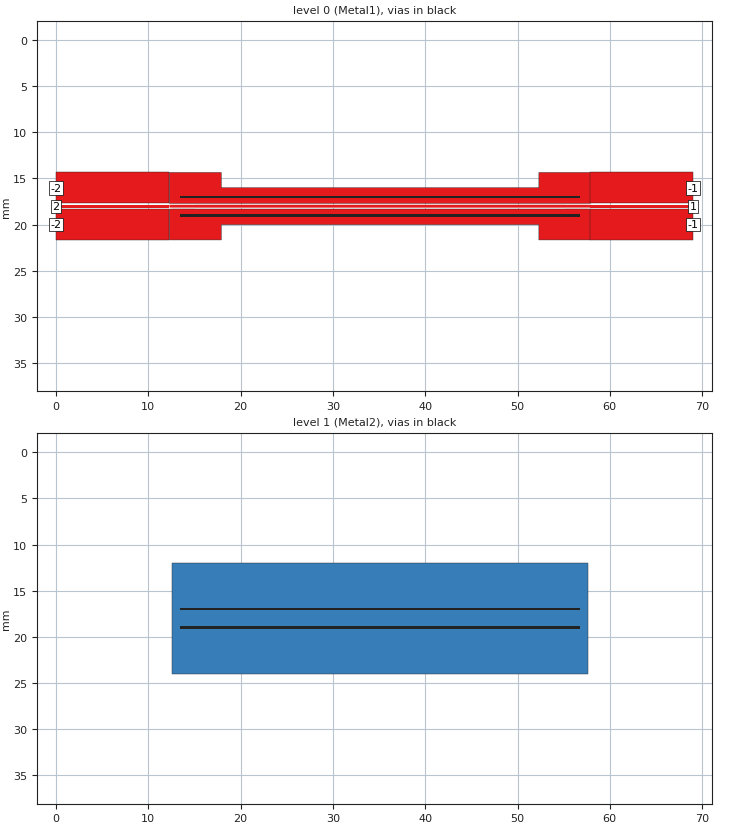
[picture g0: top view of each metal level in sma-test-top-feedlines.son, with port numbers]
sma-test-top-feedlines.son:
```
FTYP SONPROJ 18 ! Sonnet Project File
VER 17.56
HEADER
LIC antikernel2.1.50170 ac1f6b6437c5 havequick azonenberg Level3Gold
DAT 04/11/2021 07:41:37
BUILT_BY_CREATED dxf 17.52.2 05/01/2020 05:35:06
BUILT_BY_SAVED sonnet 17.56
MDATE 04/11/2021 07:41:05
HDATE 04/11/2021 07:41:05
ANN Created by dxfgeo, Sonnet Software Inc.
END HEADER
DIM
ANG DEG
CAP PF
CON /OH
FREQ GHZ
IND NH
LNG MM
RES OH
END DIM
CONTROL
VARSWP
OPTIONS  -dj
SPEED 1
CACHE_ABS 1
Q_ACC N
END CONTROL
GEO
SYM
DRP1 LEFT LINK
POLY 458 1
20
DRP1 RIGHT LINK
POLY 1025 1
0
TMET "Free Space" 0 FREESPACE 376.7303136 0 0 0
BMET "Free Space" 0 FREESPACE 376.7303136 0 0 0
MET "Copper 1oz thick" 2 TMM 58000000 0.5 0.035 2
MET "Nickel " 3 TMM 14300000 0.5 3.5e-05 2
MET "Copper 0.5oz" 1 NOR 58000000 0.5 0.0175 
MET "Unknown_metal" 1 NOR INF 0.5 0 
MET "Unknown_metal" 1 VOL INF 0
BRI "Alumina (96%)" 0 9.4 0.0004 0 
BRI "Alumina (99.5%)" 0 9.9 0.0001 0 
BRI "Aluminum Nitride" 0 8.6 0.0003 0 
BRI "Arlon 25FR" 0 3.58 0.0035 0 
BRI "Arlon 25N" 0 3.38 0.0025 0 
BRI "Arlon AD5" 0 5.1 0.003 0 
BRI "Arlon AD10" 0 10.2 0.005 0 
BRI "Arlon AD250" 0 2.5 0.0018 0 
BRI "Arlon AD255A" 0 2.55 0.0015 0 
BRI "Arlon AD260A" 0 2.6 0.0018 0 
BRI "Arlon AD270" 0 2.7 0.0023 0 
BRI "Arlon AD300A" 0 3 0.002 0 
BRI "Arlon AD320A" 0 3.2 0.0032 0 
BRI "Arlon AD350A" 0 3.5 0.003 0 
BRI "Arlon AD410" 0 4.1 0.003 0 
BRI "Arlon AD430" 0 4.3 0.003 0 
BRI "Arlon AD450" 0 4.5 0.0035 0 
BRI "Arlon AD600" 0 6.15 0.003 0 
BRI "Arlon AD1000" 0 10.2 0.0023 0 
BRI "Arlon AR1000" 0 9.8 0.003 0 
BRI "Arlon CLTE" 0 2.96 0.0023 0 
BRI "Arlon CLTE-AT" 0 3 0.0013 0 
BRI "Arlon CLTE-P" 0 2.94 0.0025 0 
BRI "Arlon CLTE-XT" 0 2.94 0.0012 0 
BRI "Arlon Cu 217LX" 0 2.17 0.0009 0 
BRI "Arlon Cu 233LX" 0 2.33 0.0013 0 
BRI "Arlon Cu 250GT" 0 2.5 0.001 0 
BRI "Arlon Cu 250GX" 0 2.5 0.0018 0 
BRI "Arlon Cu 6250" 0 2.32 0.0013 0 
BRI "Arlon Cu 6700" 0 2.35 0.0025 0 
BRI "Arlon Di 522" 0 2.5 0.001 0 
BRI "Arlon Di 527" 0 2.5 0.0018 0 
BRI "Arlon Di 870" 0 2.33 0.0013 0 
BRI "Arlon Di 880" 0 2.17 0.0009 0 
BRI "Arlon Iso 917" 0 2.17 0.0013 0 
BRI "Arlon Iso 933" 0 2.33 0.0016 0 
BRI "Arlon Multi HF" 0 3.7 0.004 0 
BRI "Arlon TC350" 0 3.5 0.002 0 
BRI "Arlon TC600" 0 6.15 0.002 0 
BRI "Beryllia (99.5%)" 0 6.5 0.0004 0 
BRI "CEM-1" 0 4.5 0.02 0 
BRI "CEM-3" 0 4.5 0.02 0 
BRI "Dupont 9K7" 0 7.1 0.0012 0 
BRI "Dupont 943" 0 7.4 0.002 0 
BRI "Dupont 951" 0 7.8 0.006 0 
BRI "Dupont FEP" 0 2 0.0005 0 
BRI "Dupont Vacrel" 0 3.8 0.011 0 
BRI "ESL 41010" 0 7.5 0.005 0 
BRI "ESL 41020" 0 7.25 0.005 0 
BRI "ESL 41050" 0 13.5 0.002 0 
BRI "ESL 41060" 0 16.5 0.002 0 
BRI "ESL 41110" 0 4.5 0.004 0 
BRI "Ferro A6M" 0 5.9 0.002 0 
BRI "Ferro A6S" 0 5.9 0.002 0 
BRI "Ferro L8" 0 7.3 0.0018 0 
BRI "FR-4" 0 4.4 0.02 0 
BRI "G-10" 0 4.8 0.025 0 
BRI "Gallium Arsenide" 0 12.9 0.006 0 
BRI "Gallium Nitride" 0 9.7 0 0 
BRI "Glass (Pyrex)" 0 4.82 0.0054 0 
BRI "Heraeus HL2000" 0 7.3 0.0026 0 
BRI "Isola 370HR" 0 4.04 0.021 0 
BRI "Isola FR408" 0 3.77 0.0116 0 
BRI "Isola FR408HR" 0 3.68 0.0092 0 
BRI "Isola Getek" 0 3.6 0.01 0 
BRI "Isola GI-180" 0 3.7 0.013 0 
BRI "Isola IS415" 0 3.82 0.0125 0 
BRI "Isola IS620i" 0 3.58 0.006 0 
BRI "Isola IS680-280" 0 2.8 0.0025 0 
BRI "Isola IS680-300" 0 3 0.003 0 
BRI "Isola IS680-320" 0 3.2 0.003 0 
BRI "Isola IS680-333" 0 3.33 0.003 0 
BRI "Isola IS680-338" 0 3.38 0.0032 0 
BRI "Isola IS680-345" 0 3.45 0.0036 0 
BRI "Kerafol CT800" 0 5.3 0.008 0 
BRI "Nelco MW9350" 0 3.7 0.004 0 
BRI "Nelco N4000-12" 0 3.7 0.008 0 
BRI "Nelco N4000-13" 0 3.7 0.009 0 
BRI "Nelco N4000-13SI" 0 3.2 0.007 0 
BRI "Nelco N4000-13EP" 0 3.7 0.008 0 
BRI "Nelco N4350-13RF" 0 3.5 0.0065 0 
BRI "Nelco N4380-13RF" 0 3.8 0.007 0 
BRI "Nelco N9300-13RF" 0 3 0.004 0 
BRI "Nelco N9320-13RF" 0 3.2 0.0045 0 
BRI "Nelco N9338-13RF" 0 3.38 0.0046 0 
BRI "Nelco N9350-13RF" 0 3.48 0.0055 0 
BRI "Nelco NH9294" 0 2.94 0.0022 0 
BRI "Nelco NH9300" 0 3 0.0023 0 
BRI "Nelco NH9320" 0 3.2 0.0024 0 
BRI "Nelco NH9338" 0 3.38 0.0025 0 
BRI "Nelco NH9348" 0 3.48 0.003 0 
BRI "Nelco NH9350" 0 3.5 0.003 0 
BRI "Nelco NH9410" 0 4.1 0.003 0 
BRI "Nelco NH9450" 0 4.5 0.003 0 
BRI "Nelco NX9240" 0 2.4 0.0016 0 
BRI "Nelco NX9245" 0 2.45 0.0016 0 
BRI "Nelco NX9250" 0 2.5 0.0017 0 
BRI "Nelco NX9255" 0 2.55 0.0018 0 
BRI "Nelco NX9260" 0 2.6 0.0019 0 
BRI "Nelco NY9208" 0 2.08 0.0006 0 
BRI "Nelco NY9217" 0 2.17 0.0008 0 
BRI "Nelco NY9220" 0 2.2 0.0009 0 
BRI "Nelco NY9233" 0 2.33 0.0011 0 
BRI "PET" 0 3.37 0.0208 0 
BRI "Polyimide" 0 3.5 0.003 0 
BRI "Quartz (Fused)" 0 3.78 0.0001 0 
BRI "Rogers 3001" 0 2.28 0.003 0 
BRI "Rogers RO2808" 0 7.6 0.0015 0 
BRI "Rogers RO3003" 0 3 0.0013 0 
BRI "Rogers RO3006" 0 6.5 0.002 0 
BRI "Rogers RO3010" 0 11.2 0.0022 0 
BRI "Rogers RO3035" 0 3.6 0.0018 0 
BRI "Rogers RO3203" 0 3.02 0.0016 0 
BRI "Rogers RO3206" 0 6.6 0.0027 0 
BRI "Rogers RO3210" 0 10.8 0.0027 0 
BRI "Rogers RO3730" 0 3 0.0016 0 
BRI "Rogers RO4003C" 0 3.55 0.0029 0 
BRI "Rogers RO4533" 0 3.45 0.0029 0 
BRI "Rogers RO4534" 0 3.4 0.003 0 
BRI "Rogers RO4350B" 0 3.66 0.0037 0 
BRI "Rogers RO4350BTX" 0 3.66 0.0034 0 
BRI "Rogers RO4360" 0 6.15 0.0038 0 
BRI "Rogers RO4450B-3.6" 0 3.3 0.0043 0 
BRI "Rogers RO4450B-4" 0 3.54 0.004 0 
BRI "Rogers RO4450F" 0 3.52 0.0041 0 
BRI "Rogers RO4730" 0 3 0.0033 0 
BRI "Rogers RT5870" 0 2.33 0.0012 0 
BRI "Rogers RT5880" 0 2.2 0.0009 0 
BRI "Rogers RT5880LZ" 0 1.96 0.0019 0 
BRI "Rogers RT6002" 0 2.94 0.0012 0 
BRI "Rogers RT6006" 0 6.15 0.0027 0 
BRI "Rogers RT6010LM" 0 10.9 0.0023 0 
BRI "Rogers RT6035HTC" 0 3.6 0.0013 0 
BRI "Rogers RT6202" 0 2.94 0.0015 0 
BRI "Rogers RT6202PR" 0 2.95 0.0015 0 
BRI "Rogers Syron7000" 0 3.4 0.0045 0 
BRI "Rogers Syron7100-2" 0 3.61 0.006 0 
BRI "Rogers Syron7100-4" 0 3.39 0.005 0 
BRI "Rogers Theta" 0 4.01 0.0118 0 
BRI "Rogers TMM 3" 0 3.39 0.002 0 
BRI "Rogers TMM 4" 0 4.5 0.002 0 
BRI "Rogers TMM 6" 0 6 0.0023 0 
BRI "Rogers TMM 10" 0 9.56 0.0022 0 
BRI "Rogers TMM 10i" 0 9.96 0.002 0 
BRI "Rogers UL2000" 0 2.5 0.0019 0 
BRI "Rogers UL3850" 0 3.05 0.0025 0 
BRI "Rogers UL3908" 0 2.9 0.0025 0 
BRI "Rogers XT8000" 0 3.34 0.0035 0 
BRI "Rogers XT8100-2" 0 3.54 0.0049 0 
BRI "Rogers XT8100-4" 0 3.32 0.0038 0 
BRI "Silicon (intrinsic)" 0 11.9 0.004 0.00044 
BRI "Silicon Dioxide" 0 3.9 0 0 
BRI "Silicon Nitride" 0 7.5 0 0 
BRI "Taconic CER-10" 0 10 0.0035 0 
BRI "Taconic FastFilm" 0 2.7 0.0012 0 
BRI "Taconic Fastrise-DS" 0 2.96 0.0018 0 
BRI "Taconic Fastrise27" 0 2.7 0.0014 0 
BRI "Taconic Fastrise77" 0 7.7 0.0034 0 
BRI "Taconic FEP" 0 2 0.0003 0 
BRI "Taconic RF-30" 0 3 0.0014 0 
BRI "Taconic RF-35" 0 3.5 0.0018 0 
BRI "Taconic RF-35A2" 0 3.5 0.0011 0 
BRI "Taconic RF-35P" 0 3.5 0.0025 0 
BRI "Taconic RF-41" 0 4.1 0.0038 0 
BRI "Taconic RF-43" 0 4.3 0.0033 0 
BRI "Taconic RF-45" 0 4.5 0.0037 0 
BRI "Taconic RF-60A" 0 6.15 0.0038 0 
BRI "Taconic RF-301" 0 2.97 0.0012 0 
BRI "Taconic TacBond HT" 0 2.35 0.0025 0 
BRI "Taconic TLA-6" 0 2.62 0.0012 0 
BRI "Taconic TLC-27" 0 2.75 0.003 0 
BRI "Taconic TLC-30" 0 3 0.003 0 
BRI "Taconic TLC-32" 0 3.2 0.003 0 
BRI "Taconic TLE-95" 0 2.95 0.0028 0 
BRI "Taconic TLF-34" 0 3.4 0.002 0 
BRI "Taconic TLF-35" 0 3.5 0.002 0 
BRI "Taconic TLP-3" 0 2.33 0.0009 0 
BRI "Taconic TLP-5" 0 2.2 0.0009 0 
BRI "Taconic TLP-5A" 0 2.17 0.0009 0 
BRI "Taconic TLT-0" 0 2.45 0.0006 0 
BRI "Taconic TLT-9" 0 2.5 0.0006 0 
BRI "Taconic TLT-8" 0 2.55 0.0006 0 
BRI "Taconic TLT-7" 0 2.6 0.0006 0 
BRI "Taconic TLT-6" 0 2.65 0.0006 0 
BRI "Taconic TLX-0" 0 2.45 0.0019 0 
BRI "Taconic TLX-9" 0 2.5 0.0019 0 
BRI "Taconic TLX-8" 0 2.55 0.0019 0 
BRI "Taconic TLX-7" 0 2.6 0.0019 0 
BRI "Taconic TLX-6" 0 2.65 0.0019 0 
BRI "Taconic TLY-3" 0 2.33 0.0009 0 
BRI "Taconic TLY-3F" 0 2.33 0.0009 0 
BRI "Taconic TLY-5" 0 2.2 0.0009 0 
BRI "Taconic TLY-5-L" 0 2.2 0.0009 0 
BRI "Taconic TLY-5A" 0 2.17 0.0009 0 
BRI "Taconic TLY-5A-L" 0 2.17 0.0009 0 
BRI "Taconic TPG-30" 0 3 0.0038 0 
BRI "Taconic TPG-32" 0 3.2 0.005 0 
BRI "Taconic TPG-35" 0 3.5 0.005 0 
BRI "Taconic TRF-41" 0 4.1 0.0035 0 
BRI "Taconic TRF-43" 0 4.3 0.0035 0 
BRI "Taconic TRF-45" 0 4.5 0.0035 0 
BRI "Taconic TSM-DS" 0 2.85 0.001 0 
BRI "Taconic TSM-DS3" 0 3 0.0011 0 
BRI "Taconic TSM-26" 0 2.6 0.0014 0 
BRI "Taconic TSM-29" 0 2.94 0.0013 0 
BRI "Taconic TSM-30" 0 3 0.0013 0 
BRI "Teflon (PTFE)" 0 2.08 0.0004 0 
BOX 3 69 36 5520 2880 20 0
      10 1 1 0 0 0 0 "Air"
      0.166 3.6 1 0.0092 0 0 0 "Isola FR408HR"
      1.4 3.6 1 0.0092 0 0 0 "Isola FR408HR"
      10 1 1 0 0 0 0 "Air"
TECHLAY METAL Metal1 BLACK -2 0 
0 0 0 N 939 1 1 100 100 0 0 0 Y
END
END
TECHLAY METAL Metal2 BLACK -3 0 
1 0 2 N 948 1 1 100 100 0 0 0 Y
END
END
TECHLAY VIA Via1 <UNSPECIFIED> -4 0 
VIA POLYGON
1 0 -1 N 1048 1 1 100 100 0 0 0 Y
TOLEVEL 0 RING NOCOVERS
END
END
VALVAR BOTLEN LNG 2 "Dim. Param."
VALVAR TOPLEN LNG 3 "Dim. Param."
DIM STD YDIR 1
POS 0.792918321 0.138719775
NOM 0.3
REF1 POLY 460 1
15
REF2 POLY 460 1
17
END
LORGN 0 36 U 
POR1 BOX
POLY 1025 1
2
-1 50 0 0 0 69 16.02 
POR1 BOX
POLY 1028 1
2
-1 50 0 0 0 69 19.98 
POR1 BOX
POLY 1030 1
2
1 50 0 0 0 69 18 
POR1 BOX
POLY 1032 1
2
-2 50 0 0 0 0 16.025 
POR1 BOX
POLY 1035 1
2
2 50 0 0 0 0 18 
POR1 BOX
POLY 1037 1
2
-2 50 0 0 0 0 19.98 
NUM 12
0 21 0 N 453 1 1 100 100 0 0 0 Y
TLAYNAM Metal1 INH
57.9 18.305
57.5625 18.305
57.5555 18.303
57.5415 18.301
55.1635 18.301
55.1525 18.303
55.1345 18.305
15.0965 18.305
15.0725 18.303
15.0585 18.301
12.6835 18.301
12.6695 18.303
12.6625 18.305
12.3 18.305
12.3 21.655
17.9125 21.655
17.9125 20
52.3125 20
52.3125 21.655
57.9 21.655
57.9 18.305
END
0 25 0 N 458 1 1 100 100 0 0 0 Y
TLAYNAM Metal1 INH
12.35 17.695
12.6625 17.695
12.6695 17.697
12.6835 17.699
15.0615 17.699
15.0725 17.697
15.0905 17.695
55.1285 17.695
55.1525 17.697
55.1665 17.699
57.5415 17.699
57.5555 17.697
57.5625 17.695
57.9 17.695
57.9 14.345
52.3125 14.345
52.3125 16
17.9125 16
17.9125 14.345
12.3125 14.345
12.3125 14.35
12.3 14.35
12.3 17.7
12.35 17.7
12.35 17.695
END
0 24 0 N 460 1 1 100 100 0 0 0 Y
TLAYNAM Metal1 INH
55.1355 18.154
55.1505 18.151
55.1535 18.15
57.9 18.15
57.9 17.85
55.1535 17.85
55.1505 17.849
55.1355 17.846
55.1205 17.845
15.1045 17.845
15.0895 17.846
15.0745 17.849
15.0715 17.85
13.1 17.85
13.1 17.85
12.3125 17.85
12.3 17.85
12.3 18.15
15.0715 18.15
15.0745 18.151
15.0895 18.154
15.1045 18.155
55.1205 18.155
55.1355 18.154
END
0 5 0 N 1025 1 1 100 100 0 0 0 Y
TLAYNAM Metal1 INH
57.9 17.695
57.9 14.345
69 14.345
69 17.695
57.9 17.695
END
0 5 0 N 1028 1 1 100 100 0 0 0 Y
TLAYNAM Metal1 INH
57.9 21.655
57.9 18.305
69 18.305
69 21.655
57.9 21.655
END
0 5 0 N 1030 1 1 100 100 0 0 0 Y
TLAYNAM Metal1 INH
57.9 18.15
57.9 17.85
69 17.85
69 18.15
57.9 18.15
END
0 5 0 N 1032 1 1 100 100 0 0 0 Y
TLAYNAM Metal1 INH
12.3 14.35
12.3 17.7
0 17.7
0 14.35
12.3 14.35
END
0 5 0 N 1035 1 1 100 100 0 0 0 Y
TLAYNAM Metal1 INH
12.3 17.85
12.3 18.15
0 18.15
0 17.85
12.3 17.85
END
0 5 0 N 1037 1 1 100 100 0 0 0 Y
TLAYNAM Metal1 INH
12.3 18.305
12.3 21.655
0 21.655
0 18.305
12.3 18.305
END
1 5 2 N 718 1 1 100 100 0 0 0 Y
TLAYNAM Metal2 INH
57.6125 12.025
12.6125 12.025
12.6125 23.975
57.6125 23.975
57.6125 12.025
END
VIA POLYGON
1 5 -1 N 473 1 1 100 100 0 0 0 Y
TOLEVEL 0 RING NOCOVERS
TLAYNAM Via1 INH
13.475 16.875
56.7325 16.875
56.7325 17.125
13.475 17.125
13.475 16.875
END
VIA POLYGON
1 5 -1 N 474 1 1 100 100 0 0 0 Y
TOLEVEL 0 RING NOCOVERS
TLAYNAM Via1 INH
13.475 18.875
56.7325 18.875
56.7325 19.125
13.475 19.125
13.475 18.875
END
END GEO
OPT
MAX 100
END OPT
VARSWP
ENABLED Y
FREQ Y AY ABS_ENTRY 0.01 16.0 -1 300 
END
END VARSWP
```
